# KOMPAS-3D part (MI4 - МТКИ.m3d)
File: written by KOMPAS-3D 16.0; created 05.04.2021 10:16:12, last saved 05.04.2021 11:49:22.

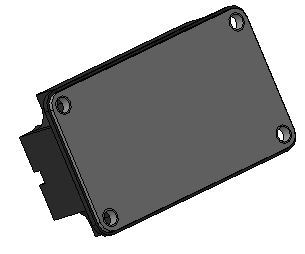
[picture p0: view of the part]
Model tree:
1. Операция без истории:1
